VERSION 5.8 ;
BUSBITCHARS "[]" ;
DIVIDERCHAR "/" ;
UNITS
    DATABASE MICRONS 1000 ;
END UNITS

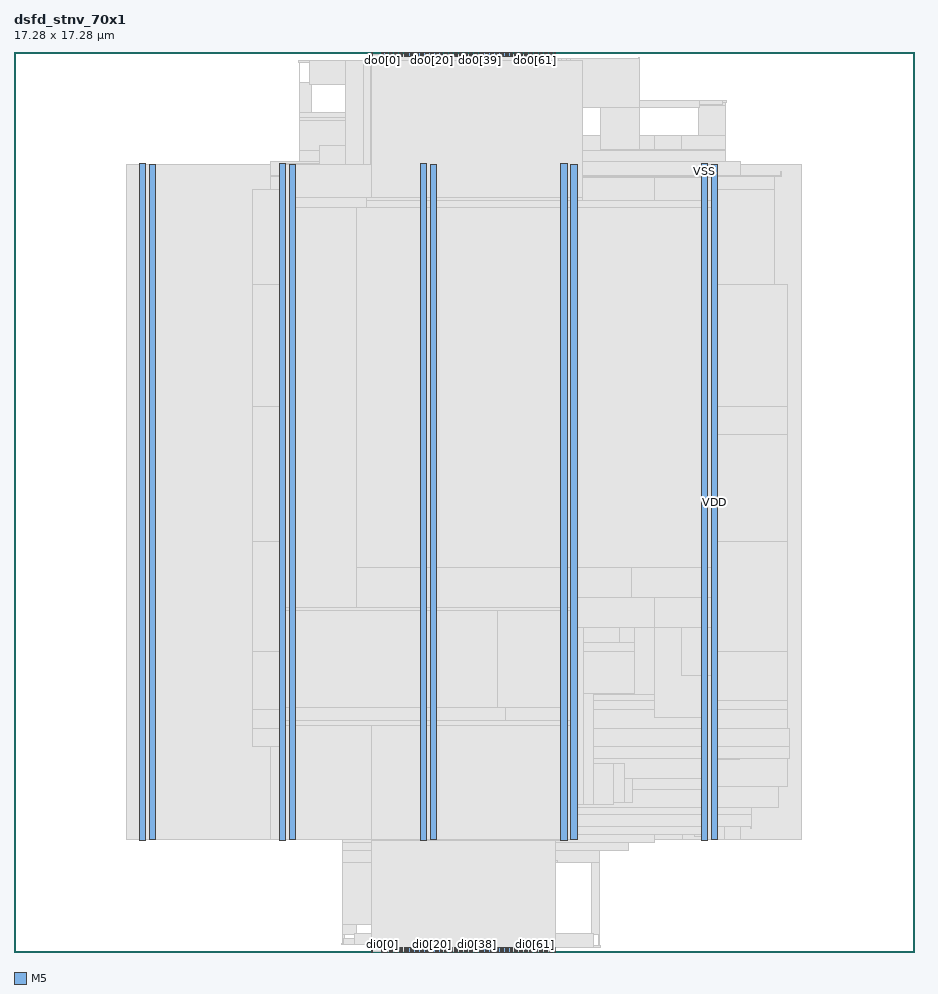
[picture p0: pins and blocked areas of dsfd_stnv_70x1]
MACRO dsfd_stnv_70x1
  FOREIGN dsfd_stnv_70x1 0 0 ;
  CLASS BLOCK ;
  SIZE 17.28 BY 17.28 ;
  PIN di0[0]
    DIRECTION INPUT ;
    USE SIGNAL ;
    PORT
      LAYER M5 ;
        RECT  7.056 0 7.08 0.084 ;
    END
  END di0[0]
  PIN di0[10]
    DIRECTION INPUT ;
    USE SIGNAL ;
    PORT
      LAYER M5 ;
        RECT  7.536 0 7.56 0.084 ;
    END
  END di0[10]
  PIN di0[11]
    DIRECTION INPUT ;
    USE SIGNAL ;
    PORT
      LAYER M5 ;
        RECT  7.584 0 7.608 0.084 ;
    END
  END di0[11]
  PIN di0[12]
    DIRECTION INPUT ;
    USE SIGNAL ;
    PORT
      LAYER M5 ;
        RECT  7.632 0 7.656 0.084 ;
    END
  END di0[12]
  PIN di0[13]
    DIRECTION INPUT ;
    USE SIGNAL ;
    PORT
      LAYER M5 ;
        RECT  7.68 0 7.704 0.084 ;
    END
  END di0[13]
  PIN di0[14]
    DIRECTION INPUT ;
    USE SIGNAL ;
    PORT
      LAYER M5 ;
        RECT  7.728 0 7.752 0.084 ;
    END
  END di0[14]
  PIN di0[15]
    DIRECTION INPUT ;
    USE SIGNAL ;
    PORT
      LAYER M5 ;
        RECT  7.776 0 7.8 0.084 ;
    END
  END di0[15]
  PIN di0[16]
    DIRECTION INPUT ;
    USE SIGNAL ;
    PORT
      LAYER M5 ;
        RECT  7.824 0 7.848 0.084 ;
    END
  END di0[16]
  PIN di0[17]
    DIRECTION INPUT ;
    USE SIGNAL ;
    PORT
      LAYER M5 ;
        RECT  7.872 0 7.896 0.084 ;
    END
  END di0[17]
  PIN di0[18]
    DIRECTION INPUT ;
    USE SIGNAL ;
    PORT
      LAYER M5 ;
        RECT  7.92 0 7.944 0.084 ;
    END
  END di0[18]
  PIN di0[19]
    DIRECTION INPUT ;
    USE SIGNAL ;
    PORT
      LAYER M5 ;
        RECT  7.968 0 7.992 0.084 ;
    END
  END di0[19]
  PIN di0[1]
    DIRECTION INPUT ;
    USE SIGNAL ;
    PORT
      LAYER M5 ;
        RECT  7.104 0 7.128 0.084 ;
    END
  END di0[1]
  PIN di0[20]
    DIRECTION INPUT ;
    USE SIGNAL ;
    PORT
      LAYER M5 ;
        RECT  8.016 0 8.04 0.084 ;
    END
  END di0[20]
  PIN di0[21]
    DIRECTION INPUT ;
    USE SIGNAL ;
    PORT
      LAYER M5 ;
        RECT  8.064 0 8.088 0.084 ;
    END
  END di0[21]
  PIN di0[22]
    DIRECTION INPUT ;
    USE SIGNAL ;
    PORT
      LAYER M5 ;
        RECT  8.112 0 8.136 0.084 ;
    END
  END di0[22]
  PIN di0[23]
    DIRECTION INPUT ;
    USE SIGNAL ;
    PORT
      LAYER M5 ;
        RECT  8.16 0 8.184 0.084 ;
    END
  END di0[23]
  PIN di0[24]
    DIRECTION INPUT ;
    USE SIGNAL ;
    PORT
      LAYER M5 ;
        RECT  8.208 0 8.232 0.084 ;
    END
  END di0[24]
  PIN di0[25]
    DIRECTION INPUT ;
    USE SIGNAL ;
    PORT
      LAYER M5 ;
        RECT  8.256 0 8.28 0.084 ;
    END
  END di0[25]
  PIN di0[26]
    DIRECTION INPUT ;
    USE SIGNAL ;
    PORT
      LAYER M5 ;
        RECT  8.304 0 8.328 0.084 ;
    END
  END di0[26]
  PIN di0[27]
    DIRECTION INPUT ;
    USE SIGNAL ;
    PORT
      LAYER M5 ;
        RECT  8.352 0 8.376 0.084 ;
    END
  END di0[27]
  PIN di0[28]
    DIRECTION INPUT ;
    USE SIGNAL ;
    PORT
      LAYER M5 ;
        RECT  8.4 0 8.424 0.084 ;
    END
  END di0[28]
  PIN di0[29]
    DIRECTION INPUT ;
    USE SIGNAL ;
    PORT
      LAYER M5 ;
        RECT  8.448 0 8.472 0.084 ;
    END
  END di0[29]
  PIN di0[2]
    DIRECTION INPUT ;
    USE SIGNAL ;
    PORT
      LAYER M5 ;
        RECT  7.152 0 7.176 0.084 ;
    END
  END di0[2]
  PIN di0[30]
    DIRECTION INPUT ;
    USE SIGNAL ;
    PORT
      LAYER M5 ;
        RECT  8.496 0 8.52 0.084 ;
    END
  END di0[30]
  PIN di0[31]
    DIRECTION INPUT ;
    USE SIGNAL ;
    PORT
      LAYER M5 ;
        RECT  8.544 0 8.568 0.084 ;
    END
  END di0[31]
  PIN di0[32]
    DIRECTION INPUT ;
    USE SIGNAL ;
    PORT
      LAYER M5 ;
        RECT  8.592 0 8.616 0.084 ;
    END
  END di0[32]
  PIN di0[33]
    DIRECTION INPUT ;
    USE SIGNAL ;
    PORT
      LAYER M5 ;
        RECT  8.64 0 8.664 0.084 ;
    END
  END di0[33]
  PIN di0[34]
    DIRECTION INPUT ;
    USE SIGNAL ;
    PORT
      LAYER M5 ;
        RECT  8.688 0 8.712 0.084 ;
    END
  END di0[34]
  PIN di0[35]
    DIRECTION INPUT ;
    USE SIGNAL ;
    PORT
      LAYER M5 ;
        RECT  8.736 0 8.76 0.084 ;
    END
  END di0[35]
  PIN di0[36]
    DIRECTION INPUT ;
    USE SIGNAL ;
    PORT
      LAYER M5 ;
        RECT  8.784 0 8.808 0.084 ;
    END
  END di0[36]
  PIN di0[37]
    DIRECTION INPUT ;
    USE SIGNAL ;
    PORT
      LAYER M5 ;
        RECT  8.832 0 8.856 0.084 ;
    END
  END di0[37]
  PIN di0[38]
    DIRECTION INPUT ;
    USE SIGNAL ;
    PORT
      LAYER M5 ;
        RECT  8.88 0 8.904 0.084 ;
    END
  END di0[38]
  PIN di0[39]
    DIRECTION INPUT ;
    USE SIGNAL ;
    PORT
      LAYER M5 ;
        RECT  8.928 0 8.952 0.084 ;
    END
  END di0[39]
  PIN di0[3]
    DIRECTION INPUT ;
    USE SIGNAL ;
    PORT
      LAYER M5 ;
        RECT  7.2 0 7.224 0.084 ;
    END
  END di0[3]
  PIN di0[40]
    DIRECTION INPUT ;
    USE SIGNAL ;
    PORT
      LAYER M5 ;
        RECT  8.976 0 9 0.084 ;
    END
  END di0[40]
  PIN di0[41]
    DIRECTION INPUT ;
    USE SIGNAL ;
    PORT
      LAYER M5 ;
        RECT  9.024 0 9.048 0.084 ;
    END
  END di0[41]
  PIN di0[42]
    DIRECTION INPUT ;
    USE SIGNAL ;
    PORT
      LAYER M5 ;
        RECT  9.072 0 9.096 0.084 ;
    END
  END di0[42]
  PIN di0[43]
    DIRECTION INPUT ;
    USE SIGNAL ;
    PORT
      LAYER M5 ;
        RECT  9.12 0 9.144 0.084 ;
    END
  END di0[43]
  PIN di0[44]
    DIRECTION INPUT ;
    USE SIGNAL ;
    PORT
      LAYER M5 ;
        RECT  9.168 0 9.192 0.084 ;
    END
  END di0[44]
  PIN di0[45]
    DIRECTION INPUT ;
    USE SIGNAL ;
    PORT
      LAYER M5 ;
        RECT  9.216 0 9.24 0.084 ;
    END
  END di0[45]
  PIN di0[46]
    DIRECTION INPUT ;
    USE SIGNAL ;
    PORT
      LAYER M5 ;
        RECT  9.264 0 9.288 0.084 ;
    END
  END di0[46]
  PIN di0[47]
    DIRECTION INPUT ;
    USE SIGNAL ;
    PORT
      LAYER M5 ;
        RECT  9.312 0 9.336 0.084 ;
    END
  END di0[47]
  PIN di0[48]
    DIRECTION INPUT ;
    USE SIGNAL ;
    PORT
      LAYER M5 ;
        RECT  9.36 0 9.384 0.084 ;
    END
  END di0[48]
  PIN di0[49]
    DIRECTION INPUT ;
    USE SIGNAL ;
    PORT
      LAYER M5 ;
        RECT  9.408 0 9.432 0.084 ;
    END
  END di0[49]
  PIN di0[4]
    DIRECTION INPUT ;
    USE SIGNAL ;
    PORT
      LAYER M5 ;
        RECT  7.248 0 7.272 0.084 ;
    END
  END di0[4]
  PIN di0[50]
    DIRECTION INPUT ;
    USE SIGNAL ;
    PORT
      LAYER M5 ;
        RECT  9.456 0 9.48 0.084 ;
    END
  END di0[50]
  PIN di0[51]
    DIRECTION INPUT ;
    USE SIGNAL ;
    PORT
      LAYER M5 ;
        RECT  9.504 0 9.528 0.084 ;
    END
  END di0[51]
  PIN di0[52]
    DIRECTION INPUT ;
    USE SIGNAL ;
    PORT
      LAYER M5 ;
        RECT  9.552 0 9.576 0.084 ;
    END
  END di0[52]
  PIN di0[53]
    DIRECTION INPUT ;
    USE SIGNAL ;
    PORT
      LAYER M5 ;
        RECT  9.6 0 9.624 0.084 ;
    END
  END di0[53]
  PIN di0[54]
    DIRECTION INPUT ;
    USE SIGNAL ;
    PORT
      LAYER M5 ;
        RECT  9.648 0 9.672 0.084 ;
    END
  END di0[54]
  PIN di0[55]
    DIRECTION INPUT ;
    USE SIGNAL ;
    PORT
      LAYER M5 ;
        RECT  9.696 0 9.72 0.084 ;
    END
  END di0[55]
  PIN di0[56]
    DIRECTION INPUT ;
    USE SIGNAL ;
    PORT
      LAYER M5 ;
        RECT  9.744 0 9.768 0.084 ;
    END
  END di0[56]
  PIN di0[57]
    DIRECTION INPUT ;
    USE SIGNAL ;
    PORT
      LAYER M5 ;
        RECT  9.792 0 9.816 0.084 ;
    END
  END di0[57]
  PIN di0[58]
    DIRECTION INPUT ;
    USE SIGNAL ;
    PORT
      LAYER M5 ;
        RECT  9.84 0 9.864 0.084 ;
    END
  END di0[58]
  PIN di0[59]
    DIRECTION INPUT ;
    USE SIGNAL ;
    PORT
      LAYER M5 ;
        RECT  9.888 0 9.912 0.084 ;
    END
  END di0[59]
  PIN di0[5]
    DIRECTION INPUT ;
    USE SIGNAL ;
    PORT
      LAYER M5 ;
        RECT  7.296 0 7.32 0.084 ;
    END
  END di0[5]
  PIN di0[60]
    DIRECTION INPUT ;
    USE SIGNAL ;
    PORT
      LAYER M5 ;
        RECT  9.936 0 9.96 0.084 ;
    END
  END di0[60]
  PIN di0[61]
    DIRECTION INPUT ;
    USE SIGNAL ;
    PORT
      LAYER M5 ;
        RECT  9.984 0 10.008 0.084 ;
    END
  END di0[61]
  PIN di0[62]
    DIRECTION INPUT ;
    USE SIGNAL ;
    PORT
      LAYER M5 ;
        RECT  10.032 0 10.056 0.084 ;
    END
  END di0[62]
  PIN di0[63]
    DIRECTION INPUT ;
    USE SIGNAL ;
    PORT
      LAYER M5 ;
        RECT  10.08 0 10.104 0.084 ;
    END
  END di0[63]
  PIN di0[64]
    DIRECTION INPUT ;
    USE SIGNAL ;
    PORT
      LAYER M5 ;
        RECT  10.128 0 10.152 0.084 ;
    END
  END di0[64]
  PIN di0[65]
    DIRECTION INPUT ;
    USE SIGNAL ;
    PORT
      LAYER M5 ;
        RECT  10.176 0 10.2 0.084 ;
    END
  END di0[65]
  PIN di0[66]
    DIRECTION INPUT ;
    USE SIGNAL ;
    PORT
      LAYER M5 ;
        RECT  10.224 0 10.248 0.084 ;
    END
  END di0[66]
  PIN di0[67]
    DIRECTION INPUT ;
    USE SIGNAL ;
    PORT
      LAYER M5 ;
        RECT  10.272 0 10.296 0.084 ;
    END
  END di0[67]
  PIN di0[68]
    DIRECTION INPUT ;
    USE SIGNAL ;
    PORT
      LAYER M5 ;
        RECT  10.32 0 10.344 0.084 ;
    END
  END di0[68]
  PIN di0[69]
    DIRECTION INPUT ;
    USE SIGNAL ;
    PORT
      LAYER M5 ;
        RECT  10.368 0 10.392 0.084 ;
    END
  END di0[69]
  PIN di0[6]
    DIRECTION INPUT ;
    USE SIGNAL ;
    PORT
      LAYER M5 ;
        RECT  7.344 0 7.368 0.084 ;
    END
  END di0[6]
  PIN di0[7]
    DIRECTION INPUT ;
    USE SIGNAL ;
    PORT
      LAYER M5 ;
        RECT  7.392 0 7.416 0.084 ;
    END
  END di0[7]
  PIN di0[8]
    DIRECTION INPUT ;
    USE SIGNAL ;
    PORT
      LAYER M5 ;
        RECT  7.44 0 7.464 0.084 ;
    END
  END di0[8]
  PIN di0[9]
    DIRECTION INPUT ;
    USE SIGNAL ;
    PORT
      LAYER M5 ;
        RECT  7.488 0 7.512 0.084 ;
    END
  END di0[9]
  PIN do0[0]
    DIRECTION OUTPUT ;
    USE SIGNAL ;
    PORT
      LAYER M5 ;
        RECT  7.056 17.196 7.08 17.28 ;
    END
  END do0[0]
  PIN do0[10]
    DIRECTION OUTPUT ;
    USE SIGNAL ;
    PORT
      LAYER M5 ;
        RECT  7.536 17.196 7.56 17.28 ;
    END
  END do0[10]
  PIN do0[11]
    DIRECTION OUTPUT ;
    USE SIGNAL ;
    PORT
      LAYER M5 ;
        RECT  7.584 17.196 7.608 17.28 ;
    END
  END do0[11]
  PIN do0[12]
    DIRECTION OUTPUT ;
    USE SIGNAL ;
    PORT
      LAYER M5 ;
        RECT  7.632 17.196 7.656 17.28 ;
    END
  END do0[12]
  PIN do0[13]
    DIRECTION OUTPUT ;
    USE SIGNAL ;
    PORT
      LAYER M5 ;
        RECT  7.68 17.196 7.704 17.28 ;
    END
  END do0[13]
  PIN do0[14]
    DIRECTION OUTPUT ;
    USE SIGNAL ;
    PORT
      LAYER M5 ;
        RECT  7.728 17.196 7.752 17.28 ;
    END
  END do0[14]
  PIN do0[15]
    DIRECTION OUTPUT ;
    USE SIGNAL ;
    PORT
      LAYER M5 ;
        RECT  7.776 17.196 7.8 17.28 ;
    END
  END do0[15]
  PIN do0[16]
    DIRECTION OUTPUT ;
    USE SIGNAL ;
    PORT
      LAYER M5 ;
        RECT  7.824 17.196 7.848 17.28 ;
    END
  END do0[16]
  PIN do0[17]
    DIRECTION OUTPUT ;
    USE SIGNAL ;
    PORT
      LAYER M5 ;
        RECT  7.872 17.196 7.896 17.28 ;
    END
  END do0[17]
  PIN do0[18]
    DIRECTION OUTPUT ;
    USE SIGNAL ;
    PORT
      LAYER M5 ;
        RECT  7.92 17.196 7.944 17.28 ;
    END
  END do0[18]
  PIN do0[19]
    DIRECTION OUTPUT ;
    USE SIGNAL ;
    PORT
      LAYER M5 ;
        RECT  7.968 17.196 7.992 17.28 ;
    END
  END do0[19]
  PIN do0[1]
    DIRECTION OUTPUT ;
    USE SIGNAL ;
    PORT
      LAYER M5 ;
        RECT  7.104 17.196 7.128 17.28 ;
    END
  END do0[1]
  PIN do0[20]
    DIRECTION OUTPUT ;
    USE SIGNAL ;
    PORT
      LAYER M5 ;
        RECT  8.016 17.196 8.04 17.28 ;
    END
  END do0[20]
  PIN do0[21]
    DIRECTION OUTPUT ;
    USE SIGNAL ;
    PORT
      LAYER M5 ;
        RECT  8.064 17.196 8.088 17.28 ;
    END
  END do0[21]
  PIN do0[22]
    DIRECTION OUTPUT ;
    USE SIGNAL ;
    PORT
      LAYER M5 ;
        RECT  8.112 17.196 8.136 17.28 ;
    END
  END do0[22]
  PIN do0[23]
    DIRECTION OUTPUT ;
    USE SIGNAL ;
    PORT
      LAYER M5 ;
        RECT  8.16 17.196 8.184 17.28 ;
    END
  END do0[23]
  PIN do0[24]
    DIRECTION OUTPUT ;
    USE SIGNAL ;
    PORT
      LAYER M5 ;
        RECT  8.208 17.196 8.232 17.28 ;
    END
  END do0[24]
  PIN do0[25]
    DIRECTION OUTPUT ;
    USE SIGNAL ;
    PORT
      LAYER M5 ;
        RECT  8.256 17.196 8.28 17.28 ;
    END
  END do0[25]
  PIN do0[26]
    DIRECTION OUTPUT ;
    USE SIGNAL ;
    PORT
      LAYER M5 ;
        RECT  8.304 17.196 8.328 17.28 ;
    END
  END do0[26]
  PIN do0[27]
    DIRECTION OUTPUT ;
    USE SIGNAL ;
    PORT
      LAYER M5 ;
        RECT  8.352 17.196 8.376 17.28 ;
    END
  END do0[27]
  PIN do0[28]
    DIRECTION OUTPUT ;
    USE SIGNAL ;
    PORT
      LAYER M5 ;
        RECT  8.4 17.196 8.424 17.28 ;
    END
  END do0[28]
  PIN do0[29]
    DIRECTION OUTPUT ;
    USE SIGNAL ;
    PORT
      LAYER M5 ;
        RECT  8.448 17.196 8.472 17.28 ;
    END
  END do0[29]
  PIN do0[2]
    DIRECTION OUTPUT ;
    USE SIGNAL ;
    PORT
      LAYER M5 ;
        RECT  7.152 17.196 7.176 17.28 ;
    END
  END do0[2]
  PIN do0[30]
    DIRECTION OUTPUT ;
    USE SIGNAL ;
    PORT
      LAYER M5 ;
        RECT  8.496 17.196 8.52 17.28 ;
    END
  END do0[30]
  PIN do0[31]
    DIRECTION OUTPUT ;
    USE SIGNAL ;
    PORT
      LAYER M5 ;
        RECT  8.544 17.196 8.568 17.28 ;
    END
  END do0[31]
  PIN do0[32]
    DIRECTION OUTPUT ;
    USE SIGNAL ;
    PORT
      LAYER M5 ;
        RECT  8.592 17.196 8.616 17.28 ;
    END
  END do0[32]
  PIN do0[33]
    DIRECTION OUTPUT ;
    USE SIGNAL ;
    PORT
      LAYER M5 ;
        RECT  8.64 17.196 8.664 17.28 ;
    END
  END do0[33]
  PIN do0[34]
    DIRECTION OUTPUT ;
    USE SIGNAL ;
    PORT
      LAYER M5 ;
        RECT  8.688 17.196 8.712 17.28 ;
    END
  END do0[34]
  PIN do0[35]
    DIRECTION OUTPUT ;
    USE SIGNAL ;
    PORT
      LAYER M5 ;
        RECT  8.736 17.196 8.76 17.28 ;
    END
  END do0[35]
  PIN do0[36]
    DIRECTION OUTPUT ;
    USE SIGNAL ;
    PORT
      LAYER M5 ;
        RECT  8.784 17.196 8.808 17.28 ;
    END
  END do0[36]
  PIN do0[37]
    DIRECTION OUTPUT ;
    USE SIGNAL ;
    PORT
      LAYER M5 ;
        RECT  8.832 17.196 8.856 17.28 ;
    END
  END do0[37]
  PIN do0[38]
    DIRECTION OUTPUT ;
    USE SIGNAL ;
    PORT
      LAYER M5 ;
        RECT  8.88 17.196 8.904 17.28 ;
    END
  END do0[38]
  PIN do0[39]
    DIRECTION OUTPUT ;
    USE SIGNAL ;
    PORT
      LAYER M5 ;
        RECT  8.928 17.196 8.952 17.28 ;
    END
  END do0[39]
  PIN do0[3]
    DIRECTION OUTPUT ;
    USE SIGNAL ;
    PORT
      LAYER M5 ;
        RECT  7.2 17.196 7.224 17.28 ;
    END
  END do0[3]
  PIN do0[40]
    DIRECTION OUTPUT ;
    USE SIGNAL ;
    PORT
      LAYER M5 ;
        RECT  8.976 17.196 9 17.28 ;
    END
  END do0[40]
  PIN do0[41]
    DIRECTION OUTPUT ;
    USE SIGNAL ;
    PORT
      LAYER M5 ;
        RECT  9.024 17.196 9.048 17.28 ;
    END
  END do0[41]
  PIN do0[42]
    DIRECTION OUTPUT ;
    USE SIGNAL ;
    PORT
      LAYER M5 ;
        RECT  9.072 17.196 9.096 17.28 ;
    END
  END do0[42]
  PIN do0[43]
    DIRECTION OUTPUT ;
    USE SIGNAL ;
    PORT
      LAYER M5 ;
        RECT  9.12 17.196 9.144 17.28 ;
    END
  END do0[43]
  PIN do0[44]
    DIRECTION OUTPUT ;
    USE SIGNAL ;
    PORT
      LAYER M5 ;
        RECT  9.168 17.196 9.192 17.28 ;
    END
  END do0[44]
  PIN do0[45]
    DIRECTION OUTPUT ;
    USE SIGNAL ;
    PORT
      LAYER M5 ;
        RECT  9.216 17.196 9.24 17.28 ;
    END
  END do0[45]
  PIN do0[46]
    DIRECTION OUTPUT ;
    USE SIGNAL ;
    PORT
      LAYER M5 ;
        RECT  9.264 17.196 9.288 17.28 ;
    END
  END do0[46]
  PIN do0[47]
    DIRECTION OUTPUT ;
    USE SIGNAL ;
    PORT
      LAYER M5 ;
        RECT  9.312 17.196 9.336 17.28 ;
    END
  END do0[47]
  PIN do0[48]
    DIRECTION OUTPUT ;
    USE SIGNAL ;
    PORT
      LAYER M5 ;
        RECT  9.36 17.196 9.384 17.28 ;
    END
  END do0[48]
  PIN do0[49]
    DIRECTION OUTPUT ;
    USE SIGNAL ;
    PORT
      LAYER M5 ;
        RECT  9.408 17.196 9.432 17.28 ;
    END
  END do0[49]
  PIN do0[4]
    DIRECTION OUTPUT ;
    USE SIGNAL ;
    PORT
      LAYER M5 ;
        RECT  7.248 17.196 7.272 17.28 ;
    END
  END do0[4]
  PIN do0[50]
    DIRECTION OUTPUT ;
    USE SIGNAL ;
    PORT
      LAYER M5 ;
        RECT  9.456 17.196 9.48 17.28 ;
    END
  END do0[50]
  PIN do0[51]
    DIRECTION OUTPUT ;
    USE SIGNAL ;
    PORT
      LAYER M5 ;
        RECT  9.504 17.196 9.528 17.28 ;
    END
  END do0[51]
  PIN do0[52]
    DIRECTION OUTPUT ;
    USE SIGNAL ;
    PORT
      LAYER M5 ;
        RECT  9.552 17.196 9.576 17.28 ;
    END
  END do0[52]
  PIN do0[53]
    DIRECTION OUTPUT ;
    USE SIGNAL ;
    PORT
      LAYER M5 ;
        RECT  9.6 17.196 9.624 17.28 ;
    END
  END do0[53]
  PIN do0[54]
    DIRECTION OUTPUT ;
    USE SIGNAL ;
    PORT
      LAYER M5 ;
        RECT  9.648 17.196 9.672 17.28 ;
    END
  END do0[54]
  PIN do0[55]
    DIRECTION OUTPUT ;
    USE SIGNAL ;
    PORT
      LAYER M5 ;
        RECT  9.696 17.196 9.72 17.28 ;
    END
  END do0[55]
  PIN do0[56]
    DIRECTION OUTPUT ;
    USE SIGNAL ;
    PORT
      LAYER M5 ;
        RECT  9.744 17.196 9.768 17.28 ;
    END
  END do0[56]
  PIN do0[57]
    DIRECTION OUTPUT ;
    USE SIGNAL ;
    PORT
      LAYER M5 ;
        RECT  9.792 17.196 9.816 17.28 ;
    END
  END do0[57]
  PIN do0[58]
    DIRECTION OUTPUT ;
    USE SIGNAL ;
    PORT
      LAYER M5 ;
        RECT  9.84 17.196 9.864 17.28 ;
    END
  END do0[58]
  PIN do0[59]
    DIRECTION OUTPUT ;
    USE SIGNAL ;
    PORT
      LAYER M5 ;
        RECT  9.888 17.196 9.912 17.28 ;
    END
  END do0[59]
  PIN do0[5]
    DIRECTION OUTPUT ;
    USE SIGNAL ;
    PORT
      LAYER M5 ;
        RECT  7.296 17.196 7.32 17.28 ;
    END
  END do0[5]
  PIN do0[60]
    DIRECTION OUTPUT ;
    USE SIGNAL ;
    PORT
      LAYER M5 ;
        RECT  9.936 17.196 9.96 17.28 ;
    END
  END do0[60]
  PIN do0[61]
    DIRECTION OUTPUT ;
    USE SIGNAL ;
    PORT
      LAYER M5 ;
        RECT  9.984 17.196 10.008 17.28 ;
    END
  END do0[61]
  PIN do0[62]
    DIRECTION OUTPUT ;
    USE SIGNAL ;
    PORT
      LAYER M5 ;
        RECT  10.032 17.196 10.056 17.28 ;
    END
  END do0[62]
  PIN do0[63]
    DIRECTION OUTPUT ;
    USE SIGNAL ;
    PORT
      LAYER M5 ;
        RECT  10.08 17.196 10.104 17.28 ;
    END
  END do0[63]
  PIN do0[64]
    DIRECTION OUTPUT ;
    USE SIGNAL ;
    PORT
      LAYER M5 ;
        RECT  10.128 17.196 10.152 17.28 ;
    END
  END do0[64]
  PIN do0[65]
    DIRECTION OUTPUT ;
    USE SIGNAL ;
    PORT
      LAYER M5 ;
        RECT  10.176 17.196 10.2 17.28 ;
    END
  END do0[65]
  PIN do0[66]
    DIRECTION OUTPUT ;
    USE SIGNAL ;
    PORT
      LAYER M5 ;
        RECT  10.224 17.196 10.248 17.28 ;
    END
  END do0[66]
  PIN do0[67]
    DIRECTION OUTPUT ;
    USE SIGNAL ;
    PORT
      LAYER M5 ;
        RECT  10.272 17.196 10.296 17.28 ;
    END
  END do0[67]
  PIN do0[68]
    DIRECTION OUTPUT ;
    USE SIGNAL ;
    PORT
      LAYER M5 ;
        RECT  10.32 17.196 10.344 17.28 ;
    END
  END do0[68]
  PIN do0[69]
    DIRECTION OUTPUT ;
    USE SIGNAL ;
    PORT
      LAYER M5 ;
        RECT  10.368 17.196 10.392 17.28 ;
    END
  END do0[69]
  PIN do0[6]
    DIRECTION OUTPUT ;
    USE SIGNAL ;
    PORT
      LAYER M5 ;
        RECT  7.344 17.196 7.368 17.28 ;
    END
  END do0[6]
  PIN do0[7]
    DIRECTION OUTPUT ;
    USE SIGNAL ;
    PORT
      LAYER M5 ;
        RECT  7.392 17.196 7.416 17.28 ;
    END
  END do0[7]
  PIN do0[8]
    DIRECTION OUTPUT ;
    USE SIGNAL ;
    PORT
      LAYER M5 ;
        RECT  7.44 17.196 7.464 17.28 ;
    END
  END do0[8]
  PIN do0[9]
    DIRECTION OUTPUT ;
    USE SIGNAL ;
    PORT
      LAYER M5 ;
        RECT  7.488 17.196 7.512 17.28 ;
    END
  END do0[9]
  PIN fi0[0]
    DIRECTION INPUT ;
    USE SIGNAL ;
    PORT
      LAYER M5 ;
        RECT  6.864 0 6.888 0.084 ;
    END
  END fi0[0]
  PIN fo0[0]
    DIRECTION OUTPUT ;
    USE SIGNAL ;
    PORT
      LAYER M5 ;
        RECT  6.864 17.196 6.888 17.28 ;
    END
  END fo0[0]
  PIN VDD
    DIRECTION INOUT ;
    USE POWER ;
    PORT
      LAYER M5 ;
        RECT  13.392 2.151 13.512 15.129 ;
        RECT  10.692 2.151 10.812 15.129 ;
        RECT  7.992 2.151 8.112 15.129 ;
        RECT  5.292 2.151 5.412 15.129 ;
        RECT  2.592 2.151 2.712 15.129 ;
    END
  END VDD
  PIN VSS
    DIRECTION INOUT ;
    USE GROUND ;
    PORT
      LAYER M5 ;
        RECT  13.2 2.137 13.32 15.143 ;
        RECT  10.5 2.137 10.62 15.143 ;
        RECT  7.8 2.137 7.92 15.143 ;
        RECT  5.1 2.137 5.22 15.143 ;
        RECT  2.4 2.137 2.52 15.143 ;
    END
  END VSS
  # OT_OBS_CLOSED layer=M5 d_um=1.536 added=9
  OBS
    LAYER RVTN ;
     RECT  2.16 2.16 15.12 2.295 ;
     RECT  2.16 2.565 15.12 2.835 ;
     RECT  2.16 3.105 15.12 3.375 ;
     RECT  2.16 3.645 15.12 3.915 ;
     RECT  2.16 4.185 15.12 4.455 ;
     RECT  2.16 4.725 15.12 4.995 ;
     RECT  2.16 5.265 15.12 5.535 ;
     RECT  2.16 5.805 15.12 6.075 ;
     RECT  2.16 6.345 15.12 6.615 ;
     RECT  2.16 6.885 15.12 7.155 ;
     RECT  2.16 7.425 15.12 7.695 ;
     RECT  2.16 7.965 15.12 8.235 ;
     RECT  2.16 8.505 15.12 8.775 ;
     RECT  2.16 9.045 15.12 9.315 ;
     RECT  2.16 9.585 15.12 9.855 ;
     RECT  2.16 10.125 15.12 10.395 ;
     RECT  2.16 10.665 15.12 10.935 ;
     RECT  2.16 11.205 15.12 11.475 ;
     RECT  2.16 11.745 15.12 12.015 ;
     RECT  2.16 12.285 15.12 12.555 ;
     RECT  2.16 12.825 15.12 13.095 ;
     RECT  2.16 13.365 15.12 13.635 ;
     RECT  2.16 13.905 15.12 14.175 ;
     RECT  2.16 14.445 15.12 14.715 ;
     RECT  2.16 14.985 15.12 15.12 ;
    LAYER RVTP ;
     RECT  2.16 2.295 15.12 2.565 ;
     RECT  2.16 2.835 15.12 3.105 ;
     RECT  2.16 3.375 15.12 3.645 ;
     RECT  2.16 3.915 15.12 4.185 ;
     RECT  2.16 4.455 15.12 4.725 ;
     RECT  2.16 4.995 15.12 5.265 ;
     RECT  2.16 5.535 15.12 5.805 ;
     RECT  2.16 6.075 15.12 6.345 ;
     RECT  2.16 6.615 15.12 6.885 ;
     RECT  2.16 7.155 15.12 7.425 ;
     RECT  2.16 7.695 15.12 7.965 ;
     RECT  2.16 8.235 15.12 8.505 ;
     RECT  2.16 8.775 15.12 9.045 ;
     RECT  2.16 9.315 15.12 9.585 ;
     RECT  2.16 9.855 15.12 10.125 ;
     RECT  2.16 10.395 15.12 10.665 ;
     RECT  2.16 10.935 15.12 11.205 ;
     RECT  2.16 11.475 15.12 11.745 ;
     RECT  2.16 12.015 15.12 12.285 ;
     RECT  2.16 12.555 15.12 12.825 ;
     RECT  2.16 13.095 15.12 13.365 ;
     RECT  2.16 13.635 15.12 13.905 ;
     RECT  2.16 14.175 15.12 14.445 ;
     RECT  2.16 14.715 15.12 14.985 ;
    LAYER M1 ;
     RECT  2.16 2.151 15.12 15.129 ;
    LAYER M2 ;
     RECT  2.16 2.151 4.927 15.129 ;
     RECT  4.927 2.151 5.899 15.174 ;
     RECT  5.899 2.151 7.259 15.21 ;
     RECT  7.259 2.151 8.843 15.174 ;
     RECT  8.843 2.151 9.211 15.129 ;
     RECT  9.211 2.106 10.003 15.129 ;
     RECT  10.003 2.07 10.255 15.129 ;
     RECT  10.255 2.034 10.435 15.669 ;
     RECT  10.435 1.962 11.795 15.669 ;
     RECT  11.795 2.106 12.299 15.669 ;
     RECT  12.299 2.151 12.839 15.669 ;
     RECT  12.839 2.151 13.639 15.129 ;
     RECT  13.639 2.151 13.955 15.174 ;
     RECT  13.955 2.151 15.12 15.129 ;
    LAYER M3 ;
     RECT  7.488 0.091 7.506 0.139 ;
     RECT  9.18 0.091 9.81 0.139 ;
     RECT  7.488 0.139 8.37 0.187 ;
     RECT  9.18 0.139 10.278 0.187 ;
     RECT  6.3 0.139 6.318 0.235 ;
     RECT  6.3 0.235 6.354 0.331 ;
     RECT  11.232 0.091 11.25 0.331 ;
     RECT  7.488 0.187 10.278 0.379 ;
     RECT  6.3 0.331 6.57 0.523 ;
     RECT  7.488 0.379 10.314 0.523 ;
     RECT  6.3 0.523 10.314 1.723 ;
     RECT  11.088 0.331 11.25 1.723 ;
     RECT  6.3 1.723 11.25 1.957 ;
     RECT  6.3 1.957 11.79 2.101 ;
     RECT  13.215 2.143 13.305 2.227 ;
     RECT  6.3 2.101 12.294 2.263 ;
     RECT  13.068 2.227 13.305 2.263 ;
     RECT  2.415 2.143 2.505 2.413 ;
     RECT  5.115 2.143 5.205 2.413 ;
     RECT  6.3 2.263 13.305 2.413 ;
     RECT  14.148 2.371 14.166 2.413 ;
     RECT  5.115 2.413 5.397 2.641 ;
     RECT  6.3 2.413 14.166 2.641 ;
     RECT  5.115 2.641 14.166 2.767 ;
     RECT  5.115 2.767 14.67 3.181 ;
     RECT  5.115 3.181 14.85 3.721 ;
     RECT  5.115 3.721 14.886 3.955 ;
     RECT  4.572 3.955 14.886 4.289 ;
     RECT  4.572 4.289 14.85 4.649 ;
     RECT  6.228 4.649 14.85 4.829 ;
     RECT  4.572 4.649 5.397 5.773 ;
     RECT  6.264 4.829 14.85 5.773 ;
     RECT  4.572 5.773 14.85 7.889 ;
     RECT  8.928 7.889 14.85 9.931 ;
     RECT  4.572 7.889 8.097 10.471 ;
     RECT  8.82 9.931 14.85 10.471 ;
     RECT  4.572 10.471 14.85 12.821 ;
     RECT  4.572 12.821 14.598 14.639 ;
     RECT  2.415 2.413 2.697 14.867 ;
     RECT  4.932 14.639 14.598 14.881 ;
     RECT  4.932 14.881 14.742 14.909 ;
     RECT  14.724 14.909 14.742 14.981 ;
     RECT  2.415 14.867 2.505 15.137 ;
     RECT  4.932 14.909 13.95 15.179 ;
     RECT  5.472 15.179 13.662 15.389 ;
     RECT  11.268 15.389 13.662 15.404 ;
     RECT  12.816 15.404 13.662 15.674 ;
     RECT  5.472 15.389 10.278 15.965 ;
     RECT  5.472 15.965 8.37 16.013 ;
     RECT  5.472 16.013 6.39 16.109 ;
     RECT  13.14 15.674 13.662 16.253 ;
     RECT  13.572 16.253 13.662 16.301 ;
     RECT  13.644 16.301 13.662 16.349 ;
     RECT  7.128 16.013 8.37 16.589 ;
     RECT  5.472 16.109 5.706 16.685 ;
     RECT  9.288 15.965 10.278 16.925 ;
     RECT  11.268 15.404 12.006 16.973 ;
     RECT  8.352 16.589 8.37 17.021 ;
     RECT  7.2 16.589 7.47 17.069 ;
     RECT  9.288 16.925 10.206 17.069 ;
     RECT  5.472 16.685 5.49 17.117 ;
     RECT  9.288 17.069 9.306 17.165 ;
     RECT  10.188 17.069 10.206 17.165 ;
     RECT  11.988 16.973 12.006 17.165 ;
    LAYER M4 ;
     RECT  2.408 2.148 2.512 15.132 ;
     RECT  2.512 2.418 2.704 14.862 ;
     RECT  5.108 2.148 5.212 15.132 ;
     RECT  5.212 2.418 5.404 15.132 ;
     RECT  5.461 17.088 5.677 17.112 ;
     RECT  5.404 14.256 5.857 15.132 ;
     RECT  6.289 0.144 6.325 0.168 ;
     RECT  5.857 14.256 6.361 15.48 ;
     RECT  5.677 16.656 6.361 17.112 ;
     RECT  5.404 5.856 6.397 6.6 ;
     RECT  6.325 0.144 6.541 0.264 ;
     RECT  6.397 5.856 6.541 7.464 ;
     RECT  6.361 14.256 6.709 17.112 ;
     RECT  5.404 3.984 6.757 4.536 ;
     RECT  6.541 5.664 6.757 7.464 ;
     RECT  6.709 13.68 6.853 17.112 ;
     RECT  6.541 0.144 6.865 0.36 ;
     RECT  6.937 1.776 7.093 1.8 ;
     RECT  6.865 0.144 7.117 0.552 ;
     RECT  7.093 1.728 7.141 1.8 ;
     RECT  7.141 1.728 7.153 1.848 ;
     RECT  7.153 1.728 7.225 1.944 ;
     RECT  7.225 1.728 7.261 2.04 ;
     RECT  6.853 12.768 7.429 17.112 ;
     RECT  7.117 0.144 7.477 0.648 ;
     RECT  6.757 3.984 7.477 7.464 ;
     RECT  7.477 0.096 7.525 0.648 ;
     RECT  7.261 1.728 7.525 2.136 ;
     RECT  7.525 0.096 7.561 2.136 ;
     RECT  7.429 12.048 7.573 17.112 ;
     RECT  7.477 3.456 7.621 7.992 ;
     RECT  7.561 0.144 7.808 2.136 ;
     RECT  7.621 3.408 7.808 7.992 ;
     RECT  7.573 12 7.808 17.112 ;
     RECT  7.808 0.144 8.003 17.112 ;
     RECT  8.003 0.144 8.051 14.862 ;
     RECT  8.003 15.84 8.099 17.112 ;
     RECT  8.051 1.728 8.104 14.862 ;
     RECT  8.104 1.728 8.201 6.84 ;
     RECT  8.051 0.144 8.339 0.744 ;
     RECT  8.201 1.728 8.387 6.696 ;
     RECT  8.339 0.144 8.531 0.696 ;
     RECT  8.387 1.728 8.572 1.896 ;
     RECT  8.099 15.936 8.581 17.112 ;
     RECT  8.572 1.728 8.597 1.8 ;
     RECT  8.581 15.936 8.957 17.16 ;
     RECT  8.531 0.144 9.125 0.552 ;
     RECT  8.387 3.408 9.205 6.696 ;
     RECT  8.104 11.04 9.205 14.472 ;
     RECT  9.205 3.408 9.299 6.888 ;
     RECT  9.205 11.04 9.301 14.52 ;
     RECT  9.301 11.04 9.541 14.712 ;
     RECT  9.457 7.872 9.589 7.896 ;
     RECT  9.589 7.68 9.601 7.896 ;
     RECT  9.733 9.648 9.74 9.672 ;
     RECT  9.601 7.68 9.829 7.992 ;
     RECT  9.74 9.12 9.829 9.672 ;
     RECT  9.299 3.408 9.889 6.6 ;
     RECT  9.889 3.216 9.961 6.6 ;
     RECT  9.125 0.096 10.172 0.552 ;
     RECT  8.597 1.728 10.172 1.752 ;
     RECT  9.541 10.992 10.241 14.76 ;
     RECT  10.172 0.096 10.259 1.752 ;
     RECT  10.259 0.096 10.325 0.408 ;
     RECT  10.259 1.728 10.433 1.752 ;
     RECT  10.241 10.992 10.453 14.856 ;
     RECT  8.957 16.224 10.453 17.16 ;
     RECT  9.961 2.88 10.508 6.6 ;
     RECT  9.829 7.68 10.508 9.672 ;
     RECT  10.453 10.992 10.508 17.16 ;
     RECT  10.508 2.148 10.612 17.16 ;
     RECT  10.612 2.418 10.685 17.16 ;
     RECT  10.685 2.418 10.804 14.862 ;
     RECT  10.804 2.832 10.937 7.416 ;
     RECT  10.804 11.376 10.945 14.76 ;
     RECT  10.945 11.424 11.027 14.76 ;
     RECT  10.325 0.096 11.117 0.36 ;
     RECT  10.937 2.832 11.117 4.968 ;
     RECT  11.117 0.096 11.261 0.12 ;
     RECT  10.804 8.496 11.269 9 ;
     RECT  11.027 11.52 11.459 14.76 ;
     RECT  11.269 8.976 11.507 9 ;
     RECT  11.117 2.832 11.513 3.624 ;
     RECT  10.937 5.952 11.629 7.416 ;
     RECT  11.513 2.88 11.729 3.624 ;
     RECT  11.729 2.88 11.873 3.336 ;
     RECT  11.117 4.944 11.905 4.968 ;
     RECT  11.629 5.952 11.905 6.84 ;
     RECT  11.459 11.664 11.941 14.76 ;
     RECT  10.685 16.224 12.017 17.16 ;
     RECT  11.905 4.944 12.301 6.84 ;
     RECT  12.017 16.224 13.169 16.344 ;
     RECT  11.873 3.12 13.208 3.336 ;
     RECT  12.301 4.512 13.208 6.84 ;
     RECT  11.941 11.664 13.208 14.856 ;
     RECT  13.208 2.148 13.312 15.132 ;
     RECT  13.312 2.418 13.504 14.862 ;
     RECT  13.169 16.272 13.601 16.344 ;
     RECT  13.601 16.32 13.673 16.344 ;
     RECT  13.504 3.696 13.925 3.72 ;
    LAYER M5 ;
     RECT  6.864 0.016 10.392 2.137 ;
     RECT  2.4 2.137 2.52 2.151 ;
     RECT  5.1 2.137 5.22 2.151 ;
     RECT  6.864 2.137 10.62 2.151 ;
     RECT  13.2 2.137 13.32 2.151 ;
     RECT  5.1 2.151 5.412 4.357 ;
     RECT  6.864 2.151 10.812 4.357 ;
     RECT  5.1 4.357 10.812 4.451 ;
     RECT  5.1 4.451 9.432 4.691 ;
     RECT  13.2 2.151 13.512 5.317 ;
     RECT  12.816 5.317 13.512 6.229 ;
     RECT  5.1 4.691 9.288 6.565 ;
     RECT  10.5 4.451 10.812 6.565 ;
     RECT  5.1 6.565 10.812 6.611 ;
     RECT  12.288 6.229 13.512 6.805 ;
     RECT  6.576 6.611 10.812 7.381 ;
     RECT  11.856 6.805 13.512 7.381 ;
     RECT  6.576 7.381 13.512 14.291 ;
     RECT  6.768 14.291 13.512 14.435 ;
     RECT  6.768 14.435 10.92 14.483 ;
     RECT  12.288 14.435 13.512 14.867 ;
     RECT  2.4 2.151 2.712 15.129 ;
     RECT  5.1 6.611 5.412 15.129 ;
     RECT  13.2 14.867 13.512 15.129 ;
     RECT  2.4 15.129 2.52 15.143 ;
     RECT  5.1 15.129 5.22 15.143 ;
     RECT  13.2 15.129 13.32 15.143 ;
     RECT  6.864 14.483 10.92 17.123 ;
     RECT  6.864 17.123 10.392 17.232 ;
     RECT  5.412 2.151 6.864 4.357 ;
     RECT  9.432 4.451 10.5 4.691 ;
     RECT  9.288 4.691 10.5 6.565 ;
     RECT  10.812 6.229 12.288 6.805 ;
     RECT  5.412 6.611 6.576 14.291 ;
     RECT  10.812 6.805 11.856 7.381 ;
     RECT  5.412 14.291 6.768 14.483 ;
     RECT  10.92 14.435 12.288 14.867 ;
     RECT  5.412 14.483 6.864 15.129 ;
  END
END dsfd_stnv_70x1
END LIBRARY
